VERSION 5.7 ;
  NOWIREEXTENSIONATPIN ON ;
  DIVIDERCHAR "/" ;
  BUSBITCHARS "[]" ;
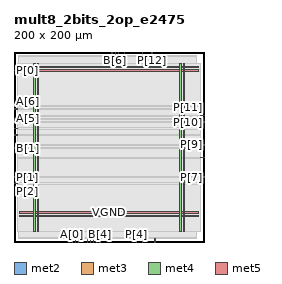
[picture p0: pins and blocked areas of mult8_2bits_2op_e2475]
MACRO mult8_2bits_2op_e2475
  CLASS BLOCK ;
  FOREIGN mult8_2bits_2op_e2475 ;
  ORIGIN 0.000 0.000 ;
  SIZE 200.000 BY 200.000 ;
  PIN A[0]
    DIRECTION INPUT ;
    USE SIGNAL ;
    ANTENNAGATEAREA 0.495000 ;
    PORT
      LAYER met2 ;
        RECT 61.270 0.000 61.550 4.000 ;
    END
  END A[0]
  PIN A[1]
    DIRECTION INPUT ;
    USE SIGNAL ;
    ANTENNAGATEAREA 0.196500 ;
    PORT
      LAYER met2 ;
        RECT 64.490 0.000 64.770 4.000 ;
    END
  END A[1]
  PIN A[2]
    DIRECTION INPUT ;
    USE SIGNAL ;
    ANTENNAGATEAREA 0.213000 ;
    PORT
      LAYER met2 ;
        RECT 83.810 0.000 84.090 4.000 ;
    END
  END A[2]
  PIN A[3]
    DIRECTION INPUT ;
    USE SIGNAL ;
    ANTENNAGATEAREA 0.196500 ;
    PORT
      LAYER met2 ;
        RECT 80.590 0.000 80.870 4.000 ;
    END
  END A[3]
  PIN A[4]
    DIRECTION INPUT ;
    USE SIGNAL ;
    ANTENNAGATEAREA 0.213000 ;
    PORT
      LAYER met2 ;
        RECT 58.050 0.000 58.330 4.000 ;
    END
  END A[4]
  PIN A[5]
    DIRECTION INPUT ;
    USE SIGNAL ;
    ANTENNAGATEAREA 0.213000 ;
    PORT
      LAYER met3 ;
        RECT 0.000 129.240 4.000 129.840 ;
    END
  END A[5]
  PIN A[6]
    DIRECTION INPUT ;
    USE SIGNAL ;
    ANTENNAGATEAREA 0.126000 ;
    PORT
      LAYER met3 ;
        RECT 0.000 139.440 4.000 140.040 ;
    END
  END A[6]
  PIN A[7]
    DIRECTION INPUT ;
    USE SIGNAL ;
    ANTENNAGATEAREA 0.126000 ;
    PORT
      LAYER met3 ;
        RECT 0.000 142.840 4.000 143.440 ;
    END
  END A[7]
  PIN B[0]
    DIRECTION INPUT ;
    USE SIGNAL ;
    ANTENNAGATEAREA 0.213000 ;
    PORT
      LAYER met2 ;
        RECT 67.710 0.000 67.990 4.000 ;
    END
  END B[0]
  PIN B[1]
    DIRECTION INPUT ;
    USE SIGNAL ;
    ANTENNAGATEAREA 0.196500 ;
    PORT
      LAYER met3 ;
        RECT 0.000 98.640 4.000 99.240 ;
    END
  END B[1]
  PIN B[2]
    DIRECTION INPUT ;
    USE SIGNAL ;
    ANTENNAGATEAREA 0.196500 ;
    PORT
      LAYER met3 ;
        RECT 0.000 112.240 4.000 112.840 ;
    END
  END B[2]
  PIN B[3]
    DIRECTION INPUT ;
    USE SIGNAL ;
    ANTENNAGATEAREA 0.213000 ;
    PORT
      LAYER met3 ;
        RECT 0.000 119.040 4.000 119.640 ;
    END
  END B[3]
  PIN B[4]
    DIRECTION INPUT ;
    USE SIGNAL ;
    ANTENNAGATEAREA 0.196500 ;
    PORT
      LAYER met2 ;
        RECT 90.250 0.000 90.530 4.000 ;
    END
  END B[4]
  PIN B[5]
    DIRECTION INPUT ;
    USE SIGNAL ;
    ANTENNAGATEAREA 0.196500 ;
    PORT
      LAYER met2 ;
        RECT 87.030 0.000 87.310 4.000 ;
    END
  END B[5]
  PIN B[6]
    DIRECTION INPUT ;
    USE SIGNAL ;
    ANTENNAGATEAREA 0.213000 ;
    PORT
      LAYER met2 ;
        RECT 106.350 196.000 106.630 200.000 ;
    END
  END B[6]
  PIN B[7]
    DIRECTION INPUT ;
    USE SIGNAL ;
    ANTENNAGATEAREA 0.213000 ;
    PORT
      LAYER met2 ;
        RECT 103.130 196.000 103.410 200.000 ;
    END
  END B[7]
  PIN P[0]
    DIRECTION OUTPUT ;
    USE SIGNAL ;
    PORT
      LAYER met3 ;
        RECT 0.000 180.240 4.000 180.840 ;
    END
  END P[0]
  PIN P[10]
    DIRECTION OUTPUT ;
    USE SIGNAL ;
    ANTENNADIFFAREA 0.891000 ;
    PORT
      LAYER met3 ;
        RECT 196.000 125.840 200.000 126.440 ;
    END
  END P[10]
  PIN P[11]
    DIRECTION OUTPUT ;
    USE SIGNAL ;
    ANTENNADIFFAREA 1.336500 ;
    PORT
      LAYER met3 ;
        RECT 196.000 132.640 200.000 133.240 ;
    END
  END P[11]
  PIN P[12]
    DIRECTION OUTPUT ;
    USE SIGNAL ;
    ANTENNADIFFAREA 1.336500 ;
    PORT
      LAYER met2 ;
        RECT 144.990 196.000 145.270 200.000 ;
    END
  END P[12]
  PIN P[13]
    DIRECTION OUTPUT ;
    USE SIGNAL ;
    ANTENNADIFFAREA 0.891000 ;
    PORT
      LAYER met2 ;
        RECT 135.330 196.000 135.610 200.000 ;
    END
  END P[13]
  PIN P[14]
    DIRECTION OUTPUT ;
    USE SIGNAL ;
    ANTENNADIFFAREA 1.336500 ;
    PORT
      LAYER met2 ;
        RECT 116.010 196.000 116.290 200.000 ;
    END
  END P[14]
  PIN P[15]
    DIRECTION OUTPUT ;
    USE SIGNAL ;
    ANTENNADIFFAREA 1.336500 ;
    PORT
      LAYER met2 ;
        RECT 109.570 196.000 109.850 200.000 ;
    END
  END P[15]
  PIN P[1]
    DIRECTION OUTPUT ;
    USE SIGNAL ;
    ANTENNADIFFAREA 0.445500 ;
    PORT
      LAYER met3 ;
        RECT 0.000 68.040 4.000 68.640 ;
    END
  END P[1]
  PIN P[2]
    DIRECTION OUTPUT ;
    USE SIGNAL ;
    ANTENNADIFFAREA 0.445500 ;
    PORT
      LAYER met3 ;
        RECT 0.000 61.240 4.000 61.840 ;
    END
  END P[2]
  PIN P[3]
    DIRECTION OUTPUT ;
    USE SIGNAL ;
    ANTENNADIFFAREA 0.445500 ;
    PORT
      LAYER met2 ;
        RECT 77.370 0.000 77.650 4.000 ;
    END
  END P[3]
  PIN P[4]
    DIRECTION OUTPUT ;
    USE SIGNAL ;
    ANTENNADIFFAREA 0.445500 ;
    PORT
      LAYER met2 ;
        RECT 128.890 0.000 129.170 4.000 ;
    END
  END P[4]
  PIN P[5]
    DIRECTION OUTPUT ;
    USE SIGNAL ;
    ANTENNADIFFAREA 0.445500 ;
    PORT
      LAYER met2 ;
        RECT 135.330 0.000 135.610 4.000 ;
    END
  END P[5]
  PIN P[6]
    DIRECTION OUTPUT ;
    USE SIGNAL ;
    ANTENNADIFFAREA 0.891000 ;
    PORT
      LAYER met2 ;
        RECT 148.210 0.000 148.490 4.000 ;
    END
  END P[6]
  PIN P[7]
    DIRECTION OUTPUT ;
    USE SIGNAL ;
    ANTENNADIFFAREA 0.891000 ;
    PORT
      LAYER met3 ;
        RECT 196.000 68.040 200.000 68.640 ;
    END
  END P[7]
  PIN P[8]
    DIRECTION OUTPUT ;
    USE SIGNAL ;
    ANTENNADIFFAREA 0.891000 ;
    PORT
      LAYER met3 ;
        RECT 196.000 88.440 200.000 89.040 ;
    END
  END P[8]
  PIN P[9]
    DIRECTION OUTPUT ;
    USE SIGNAL ;
    ANTENNADIFFAREA 1.336500 ;
    PORT
      LAYER met3 ;
        RECT 196.000 102.040 200.000 102.640 ;
    END
  END P[9]
  PIN VGND
    DIRECTION INOUT ;
    USE GROUND ;
    PORT
      LAYER met4 ;
        RECT 24.340 10.640 25.940 187.920 ;
    END
    PORT
      LAYER met4 ;
        RECT 177.940 10.640 179.540 187.920 ;
    END
    PORT
      LAYER met5 ;
        RECT 5.280 30.030 194.360 31.630 ;
    END
    PORT
      LAYER met5 ;
        RECT 5.280 183.210 194.360 184.810 ;
    END
  END VGND
  PIN VPWR
    DIRECTION INOUT ;
    USE POWER ;
    PORT
      LAYER met4 ;
        RECT 21.040 10.640 22.640 187.920 ;
    END
    PORT
      LAYER met4 ;
        RECT 174.640 10.640 176.240 187.920 ;
    END
    PORT
      LAYER met5 ;
        RECT 5.280 26.730 194.360 28.330 ;
    END
    PORT
      LAYER met5 ;
        RECT 5.280 179.910 194.360 181.510 ;
    END
  END VPWR
  OBS
      LAYER nwell ;
        RECT 5.330 10.795 194.310 187.870 ;
      LAYER li1 ;
        RECT 5.520 10.795 194.120 187.765 ;
      LAYER met1 ;
        RECT 4.210 10.640 194.120 187.920 ;
      LAYER met2 ;
        RECT 4.230 195.720 102.850 196.000 ;
        RECT 103.690 195.720 106.070 196.000 ;
        RECT 106.910 195.720 109.290 196.000 ;
        RECT 110.130 195.720 115.730 196.000 ;
        RECT 116.570 195.720 135.050 196.000 ;
        RECT 135.890 195.720 144.710 196.000 ;
        RECT 145.550 195.720 192.190 196.000 ;
        RECT 4.230 4.280 192.190 195.720 ;
        RECT 4.230 4.000 57.770 4.280 ;
        RECT 58.610 4.000 60.990 4.280 ;
        RECT 61.830 4.000 64.210 4.280 ;
        RECT 65.050 4.000 67.430 4.280 ;
        RECT 68.270 4.000 77.090 4.280 ;
        RECT 77.930 4.000 80.310 4.280 ;
        RECT 81.150 4.000 83.530 4.280 ;
        RECT 84.370 4.000 86.750 4.280 ;
        RECT 87.590 4.000 89.970 4.280 ;
        RECT 90.810 4.000 128.610 4.280 ;
        RECT 129.450 4.000 135.050 4.280 ;
        RECT 135.890 4.000 147.930 4.280 ;
        RECT 148.770 4.000 192.190 4.280 ;
      LAYER met3 ;
        RECT 3.990 181.240 196.000 187.845 ;
        RECT 4.400 179.840 196.000 181.240 ;
        RECT 3.990 143.840 196.000 179.840 ;
        RECT 4.400 142.440 196.000 143.840 ;
        RECT 3.990 140.440 196.000 142.440 ;
        RECT 4.400 139.040 196.000 140.440 ;
        RECT 3.990 133.640 196.000 139.040 ;
        RECT 3.990 132.240 195.600 133.640 ;
        RECT 3.990 130.240 196.000 132.240 ;
        RECT 4.400 128.840 196.000 130.240 ;
        RECT 3.990 126.840 196.000 128.840 ;
        RECT 3.990 125.440 195.600 126.840 ;
        RECT 3.990 120.040 196.000 125.440 ;
        RECT 4.400 118.640 196.000 120.040 ;
        RECT 3.990 113.240 196.000 118.640 ;
        RECT 4.400 111.840 196.000 113.240 ;
        RECT 3.990 103.040 196.000 111.840 ;
        RECT 3.990 101.640 195.600 103.040 ;
        RECT 3.990 99.640 196.000 101.640 ;
        RECT 4.400 98.240 196.000 99.640 ;
        RECT 3.990 89.440 196.000 98.240 ;
        RECT 3.990 88.040 195.600 89.440 ;
        RECT 3.990 69.040 196.000 88.040 ;
        RECT 4.400 67.640 195.600 69.040 ;
        RECT 3.990 62.240 196.000 67.640 ;
        RECT 4.400 60.840 196.000 62.240 ;
        RECT 3.990 10.715 196.000 60.840 ;
  END
END mult8_2bits_2op_e2475
END LIBRARY

